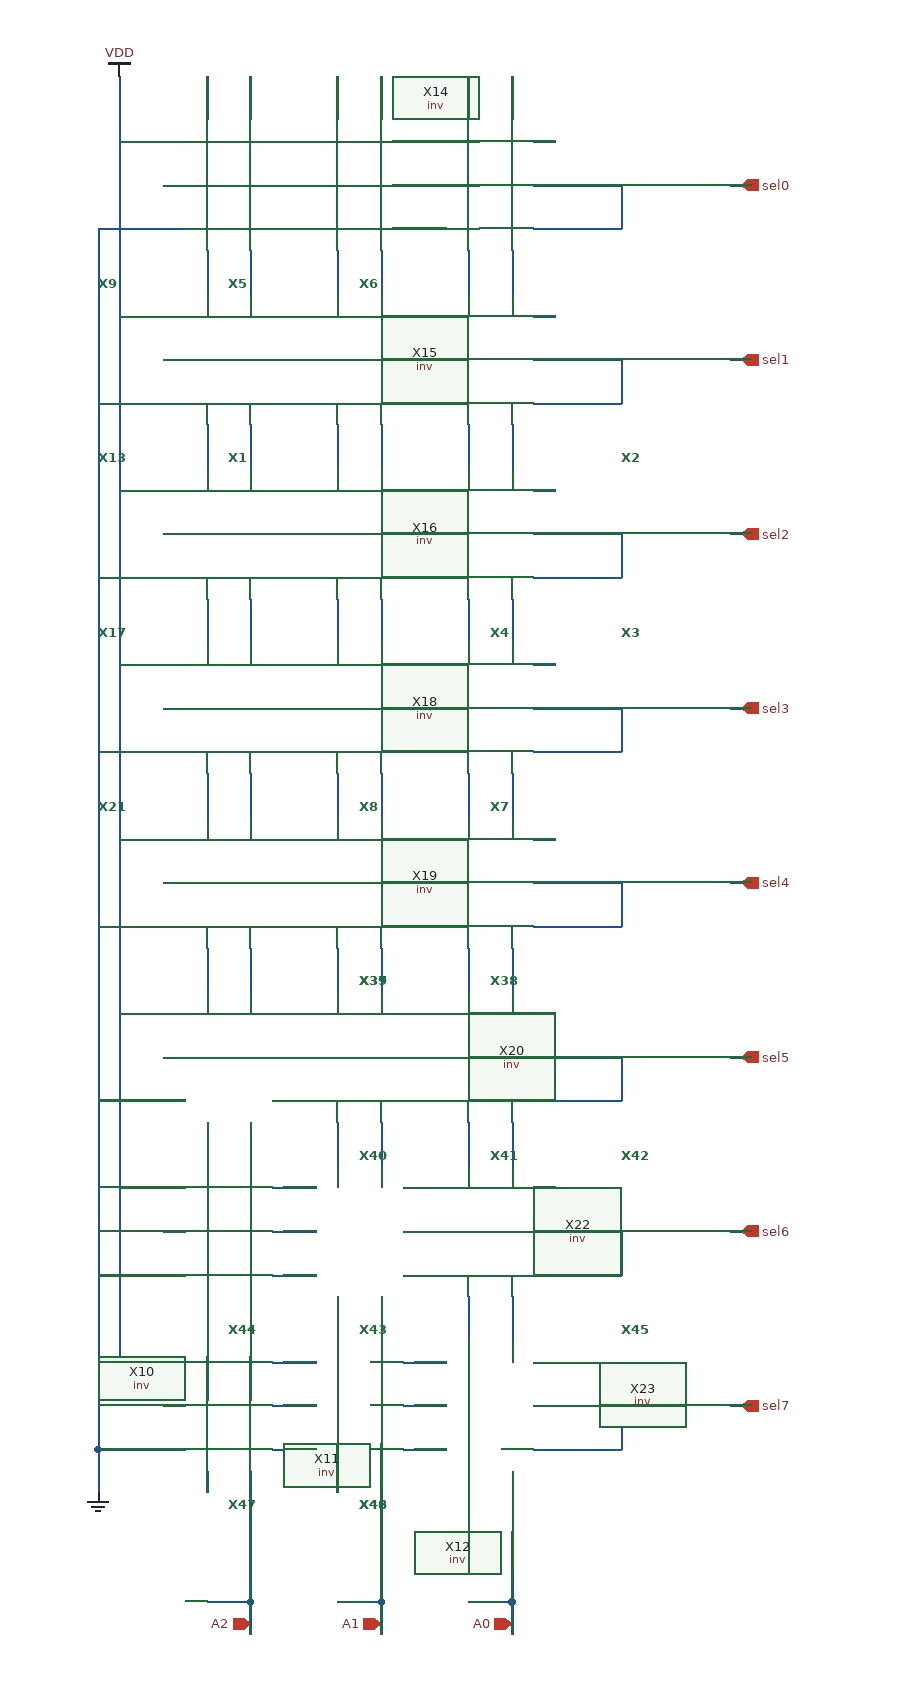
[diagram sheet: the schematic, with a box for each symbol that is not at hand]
v {xschem version=2.9.9 file_version=1.2 }
G {}
K {}
V {}
S {}
E {}
N 7190 5960 7210 5960 { lab=sel7}
N 7190 5800 7210 5800 { lab=sel6}
N 7190 5640 7210 5640 { lab=sel5}
N 7190 5480 7210 5480 { lab=sel4}
N 7190 5320 7210 5320 { lab=sel3}
N 7190 5160 7210 5160 { lab=sel2}
N 7190 5000 7210 5000 { lab=sel1}
N 7190 4840 7210 4840 { lab=sel0}
N 6770 4800 6810 4800 { lab=#net1}
N 6770 4840 6810 4840 { lab=#net2}
N 6770 4880 6810 4880 { lab=#net3}
N 6890 4800 6930 4800 { lab=#net4}
N 6890 4840 6930 4840 { lab=#net5}
N 6890 4880 6930 4880 { lab=#net6}
N 7010 4840 7030 4840 { lab=#net7}
N 7010 4880 7030 4880 { lab=#net7}
N 6710 4900 6710 4940 { lab=#net8}
N 6750 4900 6750 4940 { lab=#net9}
N 6830 4900 6830 4940 { lab=#net10}
N 6870 4900 6870 4940 { lab=#net11}
N 6950 4900 6950 4940 { lab=#net12}
N 6990 4900 6990 4940 { lab=#net13}
N 6770 4960 6810 4960 { lab=#net14}
N 6770 5000 6810 5000 { lab=#net15}
N 6770 5040 6810 5040 { lab=#net16}
N 6890 4960 6930 4960 { lab=#net17}
N 6890 5000 6930 5000 { lab=#net18}
N 6890 5040 6930 5040 { lab=#net19}
N 7010 5000 7030 5000 { lab=#net20}
N 7010 5040 7030 5040 { lab=#net21}
N 6710 5060 6710 5100 { lab=#net22}
N 6750 5060 6750 5100 { lab=#net23}
N 6830 5060 6830 5100 { lab=#net24}
N 6870 5060 6870 5100 { lab=#net25}
N 6950 5060 6950 5100 { lab=#net26}
N 6990 5060 6990 5100 { lab=#net27}
N 6770 5120 6810 5120 { lab=#net28}
N 6770 5160 6810 5160 { lab=#net29}
N 6770 5200 6810 5200 { lab=#net30}
N 6890 5120 6930 5120 { lab=#net31}
N 6890 5160 6930 5160 { lab=#net32}
N 6890 5200 6930 5200 { lab=#net33}
N 7010 5160 7030 5160 { lab=#net34}
N 7010 5200 7030 5200 { lab=#net35}
N 6710 5220 6710 5260 { lab=#net36}
N 6750 5220 6750 5260 { lab=#net37}
N 6830 5220 6830 5260 { lab=#net38}
N 6870 5220 6870 5260 { lab=#net39}
N 6950 5220 6950 5260 { lab=#net40}
N 6990 5220 6990 5260 { lab=#net41}
N 6770 5280 6810 5280 { lab=#net42}
N 6770 5320 6810 5320 { lab=#net43}
N 6770 5360 6810 5360 { lab=#net44}
N 6890 5280 6930 5280 { lab=#net45}
N 6890 5320 6930 5320 { lab=#net46}
N 6890 5360 6930 5360 { lab=#net47}
N 7010 5320 7030 5320 { lab=#net48}
N 7010 5360 7030 5360 { lab=#net49}
N 6710 5380 6710 5420 { lab=#net50}
N 6750 5380 6750 5420 { lab=#net51}
N 6830 5380 6830 5420 { lab=#net52}
N 6870 5380 6870 5420 { lab=#net53}
N 6950 5380 6950 5420 { lab=#net54}
N 6990 5380 6990 5420 { lab=#net55}
N 6770 5440 6810 5440 { lab=#net56}
N 6770 5480 6810 5480 { lab=#net57}
N 6770 5520 6810 5520 { lab=#net58}
N 6890 5440 6930 5440 { lab=#net59}
N 6890 5480 6930 5480 { lab=#net60}
N 6890 5520 6930 5520 { lab=#net61}
N 7010 5480 7030 5480 { lab=#net62}
N 7010 5520 7030 5520 { lab=#net63}
N 6710 5540 6710 5580 { lab=#net64}
N 6750 5540 6750 5580 { lab=#net65}
N 6830 5540 6830 5580 { lab=#net66}
N 6870 5540 6870 5580 { lab=#net67}
N 6950 5540 6950 5580 { lab=#net68}
N 6990 5540 6990 5580 { lab=#net69}
N 6770 5600 6810 5600 { lab=#net70}
N 6770 5640 6810 5640 { lab=#net71}
N 6770 5680 6810 5680 { lab=#net72}
N 6890 5600 6930 5600 { lab=#net73}
N 6890 5640 6930 5640 { lab=#net74}
N 6890 5680 6930 5680 { lab=#net75}
N 7010 5640 7030 5640 { lab=#net76}
N 7010 5680 7030 5680 { lab=#net77}
N 6710 5700 6710 5740 { lab=#net78}
N 6750 5700 6750 5740 { lab=#net79}
N 6830 5700 6830 5740 { lab=#net80}
N 6870 5700 6870 5740 { lab=#net81}
N 6950 5700 6950 5740 { lab=#net82}
N 6990 5700 6990 5740 { lab=#net83}
N 6770 5760 6810 5760 { lab=#net84}
N 6770 5800 6810 5800 { lab=#net85}
N 6770 5840 6810 5840 { lab=#net86}
N 6890 5760 6930 5760 { lab=#net87}
N 6890 5800 6930 5800 { lab=#net88}
N 6890 5840 6930 5840 { lab=#net89}
N 7010 5800 7030 5800 { lab=#net90}
N 7010 5840 7030 5840 { lab=#net91}
N 6710 5860 6710 5900 { lab=#net92}
N 6750 5860 6750 5900 { lab=#net93}
N 6830 5860 6830 5900 { lab=#net94}
N 6870 5860 6870 5900 { lab=#net95}
N 6950 5860 6950 5900 { lab=#net96}
N 6990 5860 6990 5900 { lab=#net97}
N 6770 5920 6810 5920 { lab=#net98}
N 6770 5960 6810 5960 { lab=#net99}
N 6770 6000 6810 6000 { lab=#net100}
N 6890 5920 6930 5920 { lab=#net101}
N 6890 5960 6930 5960 { lab=#net102}
N 6890 6000 6930 6000 { lab=#net103}
N 7010 5960 7030 5960 { lab=#net104}
N 7010 6000 7030 6000 { lab=#net105}
N 6710 4740 6710 4780 { lab=#net106}
N 6750 4740 6750 4780 { lab=#net107}
N 6830 4740 6830 4780 { lab=#net108}
N 6870 4740 6870 4780 { lab=#net109}
N 6950 4740 6950 4780 { lab=#net110}
N 6990 4740 6990 4780 { lab=#net111}
N 7010 4800 7030 4800 { lab=#net112}
N 7010 4960 7030 4960 { lab=#net113}
N 7010 5120 7030 5120 { lab=#net114}
N 7010 5280 7030 5280 { lab=#net115}
N 7010 5440 7030 5440 { lab=#net116}
N 7010 5600 7030 5600 { lab=#net117}
N 7010 5760 7030 5760 { lab=#net118}
N 7010 5920 7030 5920 { lab=#net119}
N 6630 4740 6630 4780 { lab=VDD}
N 6750 6140 6750 6170 { lab=A2}
N 6870 6140 6870 6170 { lab=A1}
N 6990 6140 6990 6170 { lab=A0}
N 6710 6020 6710 6040 { lab=#net120}
N 6750 6020 6750 6040 { lab=A2}
N 6830 6020 6830 6040 { lab=#net121}
N 6870 6020 6870 6040 { lab=A1}
N 6950 6020 6950 6040 { lab=#net122}
N 6990 6020 6990 6040 { lab=A0}
N 6650 5920 6690 5920 { lab=VDD}
N 6650 6000 6690 6000 { lab=GND}
N 6650 5760 6690 5760 { lab=VDD}
N 6650 5840 6690 5840 { lab=GND}
N 6650 5600 6690 5600 { lab=VDD}
N 6650 5680 6690 5680 { lab=GND}
N 6650 5440 6690 5440 { lab=VDD}
N 6650 5520 6690 5520 { lab=GND}
N 6650 5360 6690 5360 { lab=GND}
N 6650 5280 6690 5280 { lab=VDD}
N 6650 5200 6690 5200 { lab=GND}
N 6650 5120 6690 5120 { lab=VDD}
N 6650 5040 6690 5040 { lab=GND}
N 6650 4960 6690 4960 { lab=VDD}
N 6650 4800 6690 4800 { lab=VDD}
N 6650 4880 6690 4880 { lab=GND}
N 6670 4840 6690 4840 { lab=#net123}
N 6670 5000 6690 5000 { lab=#net124}
N 6670 5160 6690 5160 { lab=#net125}
N 6670 5320 6690 5320 { lab=#net126}
N 6670 5480 6690 5480 { lab=#net127}
N 6670 5640 6690 5640 { lab=#net128}
N 6670 5800 6690 5800 { lab=#net129}
N 6670 5960 6690 5960 { lab=#net130}
N 6710 6140 6750 6140 { lab=A2}
N 6750 6040 6750 6140 { lab=A2}
N 6830 6140 6870 6140 { lab=A1}
N 6870 6040 6870 6140 { lab=A1}
N 6950 6140 6990 6140 { lab=A0}
N 6990 6040 6990 6140 { lab=A0}
N 6630 4780 6630 5920 { lab=VDD}
N 6630 5920 6650 5920 { lab=VDD}
N 6610 6000 6650 6000 { lab=GND}
N 6610 6000 6610 6040 { lab=GND}
N 6610 4880 6610 6000 { lab=GND}
N 6610 4880 6650 4880 { lab=GND}
N 6630 4800 6650 4800 { lab=VDD}
N 6630 4960 6650 4960 { lab=VDD}
N 6610 5040 6650 5040 { lab=GND}
N 6630 5120 6650 5120 { lab=VDD}
N 6610 5200 6650 5200 { lab=GND}
N 6630 5280 6650 5280 { lab=VDD}
N 6610 5360 6650 5360 { lab=GND}
N 6630 5440 6650 5440 { lab=VDD}
N 6610 5520 6640 5520 { lab=GND}
N 6640 5520 6650 5520 { lab=GND}
N 6630 5600 6650 5600 { lab=VDD}
N 6610 5680 6650 5680 { lab=GND}
N 6630 5760 6650 5760 { lab=VDD}
N 6610 5840 6650 5840 { lab=GND}
N 7030 4840 7090 4840 { lab=#net7}
N 7090 4840 7090 4880 { lab=#net7}
N 7030 4880 7090 4880 { lab=#net7}
N 7030 5960 7090 5960 {}
N 7090 5960 7090 6000 {}
N 7030 6000 7090 6000 {}
N 7030 5840 7090 5840 {}
N 7090 5800 7090 5840 {}
N 7030 5800 7090 5800 {}
N 7030 5640 7090 5640 {}
N 7090 5640 7090 5680 {}
N 7030 5680 7090 5680 {}
N 7030 5480 7090 5480 {}
N 7090 5480 7090 5520 {}
N 7030 5520 7090 5520 {}
N 7030 5320 7090 5320 {}
N 7090 5320 7090 5360 {}
N 7030 5360 7090 5360 {}
N 7030 5160 7090 5160 {}
N 7090 5160 7090 5200 {}
N 7030 5200 7090 5200 {}
N 7030 5000 7090 5000 {}
N 7090 5000 7090 5040 {}
N 7030 5040 7090 5040 {}
C {decoder/decoder_cell_0.sym} 6730 4930 0 0 {name=X5}
C {decoder/decoder_cell_0.sym} 6850 4930 0 0 {name=X6}
C {decoder/decoder_cell_0.sym} 6730 5090 0 0 {name=X1}
C {decoder/decoder_cell_0.sym} 7090 5090 0 1 {name=X2}
C {decoder/decoder_cell_0.sym} 7090 5250 0 1 {name=X3}
C {decoder/decoder_cell_0.sym} 6970 5250 0 1 {name=X4}
C {decoder/decoder_cell_0.sym} 6970 5410 0 1 {name=X7}
C {decoder/decoder_cell_0.sym} 6850 5410 0 0 {name=X8}
C {decoder/decoder_cell_0.sym} 6610 4930 0 0 {name=X9}
C {decoder/decoder_cell_0.sym} 6610 5090 0 0 {name=X13}
C {decoder/decoder_cell_0.sym} 6610 5250 0 0 {name=X17}
C {decoder/decoder_cell_0.sym} 6610 5410 0 0 {name=X21}
C {decoder/decoder_cell_0.sym} 6850 5570 0 1 {name=X37}
C {decoder/decoder_cell_0.sym} 6970 5570 0 1 {name=X38}
C {decoder/decoder_cell_0.sym} 6850 5570 0 0 {name=X39}
C {decoder/decoder_cell_0.sym} 6850 5730 0 1 {name=X40}
C {decoder/decoder_cell_0.sym} 6970 5730 0 1 {name=X41}
C {decoder/decoder_cell_0.sym} 7090 5730 0 1 {name=X42}
C {decoder/decoder_cell_0.sym} 6850 5890 0 1 {name=X43}
C {decoder/decoder_cell_0.sym} 6730 5890 0 0 {name=X44}
C {decoder/decoder_cell_0.sym} 7090 5890 0 1 {name=X45}
C {decoder/decoder_cell_0.sym} 6850 6050 0 1 {name=X46}
C {decoder/decoder_cell_0.sym} 6730 6050 0 0 {name=X47}
C {decoder/decoder_cell_0.sym} 6850 6050 0 0 {name=X48}
C {devices/opin.sym} 7200 5960 0 0 {name=p65 lab=sel7}
C {devices/opin.sym} 7200 5800 0 0 {name=p66 lab=sel6}
C {devices/opin.sym} 7200 5640 0 0 {name=p67 lab=sel5}
C {devices/opin.sym} 7200 5480 0 0 {name=p68 lab=sel4}
C {devices/opin.sym} 7200 5320 0 0 {name=p69 lab=sel3}
C {devices/opin.sym} 7200 5160 0 0 {name=p70 lab=sel2}
C {devices/opin.sym} 7200 5000 0 0 {name=p71 lab=sel1}
C {devices/opin.sym} 7200 4840 0 0 {name=p72 lab=sel0}
C {devices/ipin.sym} 6750 6160 3 0 {name=p6 lab=A2}
C {devices/ipin.sym} 6870 6160 3 0 {name=p7 lab=A1}
C {devices/ipin.sym} 6990 6160 3 0 {name=p8 lab=A0}
C {inv/inv.sym} 6710 6090 3 0 {name=X10}
C {inv/inv.sym} 6830 6090 3 0 {name=X11}
C {inv/inv.sym} 6950 6090 3 0 {name=X12}
C {devices/vdd.sym} 6630 4740 0 0 {name=l1 lab=VDD}
C {devices/gnd.sym} 6610 6040 0 0 {name=l2 lab=GND}
C {inv/inv.sym} 7140 4840 0 0 {name=X14 Wpmos=3 Lpmos=0.18 Wnmos=1 Lnmos=0.18}
C {inv/inv.sym} 7140 5000 0 0 {name=X15 Wpmos=3 Lpmos=0.18 Wnmos=1 Lnmos=0.18}
C {inv/inv.sym} 7140 5160 0 0 {name=X16 Wpmos=3 Lpmos=0.18 Wnmos=1 Lnmos=0.18}
C {inv/inv.sym} 7140 5320 0 0 {name=X18 Wpmos=3 Lpmos=0.18 Wnmos=1 Lnmos=0.18}
C {inv/inv.sym} 7140 5480 0 0 {name=X19 Wpmos=3 Lpmos=0.18 Wnmos=1 Lnmos=0.18}
C {inv/inv.sym} 7140 5640 0 0 {name=X20 Wpmos=3 Lpmos=0.18 Wnmos=1 Lnmos=0.18}
C {inv/inv.sym} 7140 5800 0 0 {name=X22 Wpmos=3 Lpmos=0.18 Wnmos=1 Lnmos=0.18}
C {inv/inv.sym} 7140 5960 0 0 {name=X23 Wpmos=3 Lpmos=0.18 Wnmos=1 Lnmos=0.18}
